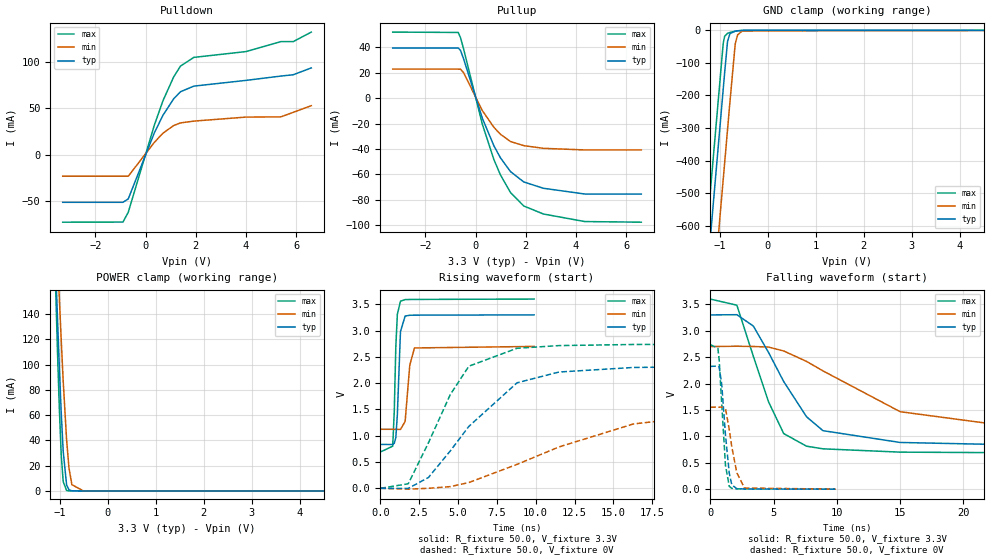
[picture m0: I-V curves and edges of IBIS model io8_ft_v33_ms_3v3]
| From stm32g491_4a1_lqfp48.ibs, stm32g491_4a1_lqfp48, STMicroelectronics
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[Model]   io8_ft_v33_ms_3v3
Model_type I/O
Polarity   Non-Inverting
Enable   Active-Low
| CAP_THRESHOLD on pad IOFT is "UDTCAPC" :
| Rising=30.0% of vddiom   Falling=70.0% of vddiom
| C_comp min and max val. don't necessarily correlate with the min and max pvt
| but are the smallest and greatest pad capacitance found.
| var   typ   min   max
C_comp   2.27946pF  2.25176pF  2.68147pF
|C_comp_pullup   1.26022pF  1.27543pF  1.50397pF
|C_comp_pulldown   1.01925pF  976.33215fF  1.17749pF
Vinl = 810.0mV
Vinh = 2.52V
Vmeas = 1.65V   | Reference voltage for timing measurements
Cref  = 50.0pF   | Timing specification test load capacitance value
Rref  = 100.0MOhm   | Timing specification test load resistance value
Vref  = 1.65V   | Timing specification test load voltage
[Model Spec]
| TIME_THRESHOLD on pin ZIV33M is "CMOS" :
| Rising=50.0% of vddiom   Falling=50.0% of vddiom
Vinl 1.34770V 1.11470V 1.44970V
Vinh 1.77530V 1.49030V 1.90330V
| variable   typ   min   max
[Temperature Range] 25.0 140.0 -40.0
| variable   typ   min   max
[Voltage Range] 3.3V 2.7V 3.6V
| variable   typ   min   max
[POWER Clamp Reference] 3.3V 2.7V 3.6V
| variable   typ   min   max
[GND Clamp Reference] 0V 0V 0V
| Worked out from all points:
|   slope of the pulldown table from 0 to 0.495 V, typ, clamps not added: 15.6 ohm
|   slope of the pullup table from 0 to 0.495 V, typ, clamps not added: 18.1 ohm
|   GND clamp passes 1 mA (typ) near -0.60 V on its own axis
|   POWER clamp passes 1 mA (typ) near -0.81 V on its own axis
|   rising waveform, R_fixture 50.0, V_fixture 3.3V: 20-80 % time 190ps typ, 251ps min, 181ps max; typ from 0.835 V to 3.3 V
|   falling waveform, R_fixture 50.0, V_fixture 3.3V: 20-80 % time 3.64ns typ, 7.54ns min, 2.48ns max; typ from 3.3 V to 0.835 V
|   rising waveform, R_fixture 50.0, V_fixture 0V: 20-80 % time 4.13ns typ, 8.94ns min, 2.71ns max; typ from 0 V to 2.33 V
|   falling waveform, R_fixture 50.0, V_fixture 0V: 20-80 % time 472ps typ, 664ps min, 394ps max; typ from 2.33 V to 0 V
[POWER Clamp]
-3.3V     2.991A     2.546A     3.694A
-1.11V    202.2mA    242.3mA    190.9mA
-1.09V    180mA      223.6mA    163.4mA
-1.05V    136.9mA    187mA      110.9mA
-1.01V    96.55mA    151.6mA    64.02mA
-970mV    60.39mA    117.9mA    27.41mA
-930mV    31.08mA    86.54mA    7.282mA
-860mV    4.779mA    40.5mA     315.2uA
-810mV    823.2uA    18.15mA    29.21uA
-750mV    88.98uA    4.952mA    1.667uA
-510mV    11.25nA    8.405uA    48.77pA
6.6V      0A         0A         0A
[GND Clamp]
-3.3V     -4.209A    -4.487A    -4.067A
-1.41V    -996.3mA   -1.274A    -854.3mA
-1.25V    -724.3mA   -1.002A    -582.3mA
-1.21V    -656.3mA   -933.6mA   -514.3mA
-930mV    -180.3mA   -457.6mA   -39.53mA
-900mV    -129.3mA   -406.6mA   -18.05mA
-840mV    -33.79mA   -304.6mA   -9.105mA
-790mV    -10.15mA   -219.6mA   -6.665mA
-680mV    -2.476mA   -41.57mA   -2.768mA
-630mV    -1.406mA   -13.77mA   -1.51mA
-530mV    -268.4uA   -1.762mA   -214.9uA
6.6V      830.6pA    196nA      594.5pA
| variable   typ   min   max
[Pullup Reference] 3.3V 2.7V 3.6V
| variable   typ   min   max
[Pulldown Reference] 0V 0V 0V
[Pullup]
-3.3V     39.39mA    22.76mA    51.9mA
-690mV    39.39mA    22.76mA    51.61mA
-600mV    37.53mA    22.73mA    47.48mA
-480mV    31mA       20.05mA    38.86mA
270mV     -15.88mA   -9.861mA   -20.62mA
730mV     -37.54mA   -23mA      -48.39mA
990mV     -46.97mA   -28.45mA   -60.4mA
1.39V     -57.81mA   -34.14mA   -74.25mA
1.92V     -65.96mA   -37.41mA   -84.89mA
2.7V      -70.92mA   -39.51mA   -91.15mA
4.35V     -75.45mA   -40.79mA   -97.1mA
6.6V      -75.45mA   -40.79mA   -97.6mA
[Pulldown]
-3.3V     -51.64mA   -23.39mA   -73.18mA
-900mV    -51.64mA   -23.39mA   -73.04mA
-690mV    -47.97mA   -23.39mA   -62.4mA
350mV     23.63mA    13.27mA    31.99mA
690mV     42.49mA    23.17mA    58.21mA
1.12V     60.48mA    31.51mA    84.25mA
1.39V     68.1mA     34.34mA    95.86mA
1.92V     74.17mA    36.28mA    105.3mA
4V        80.41mA    40.64mA    111.6mA
5.39V     85.07mA    40.9mA     122.4mA
5.88V     86.5mA     45.8mA     122.4mA
6.6V      93.9mA     53mA       132.7mA
[Ramp]
dV/dt_r 1.39485V/4.12939ns 931.93273mV/8.94234ns 1.64323V/2.70823ns
dV/dt_f 1.47908V/3.63556ns 946.45341mV/7.54066ns 1.74612V/2.48315ns
R_load = 50.0
| Removed startup time: 0s 0s 0s  .
| Removed end time: 9.9ns.
[Rising Waveform]
R_fixture   = 50.0
V_fixture   = 3.3V
V_fixture_min = 2.7V
V_fixture_max = 3.6V
0s        834.8mV    1.123V     689.8mV
800ps     833mV      1.123V     801.4mV
900ps     856.7mV    1.122V     1.463V
1ns       961.6mV    1.122V     2.691V
1.1ns     1.408V     1.121V     3.312V
1.3ns     2.983V     1.119V     3.56V
1.6ns     3.277V     1.273V     3.59V
1.9ns     3.292V     2.344V     3.592V
2.2ns     3.294V     2.67V      3.593V
9.9ns     3.299V     2.699V     3.6V
| Removed startup time: 0s 0s 0s  .
| Removed end time: 99.9ns.
[Falling Waveform]
R_fixture   = 50.0
V_fixture   = 3.3V
V_fixture_min = 2.7V
V_fixture_max = 3.6V
0s        3.3V       2.7V       3.6V
2.1ns     3.304V     2.707V     3.484V
3.4ns     3.089V     2.702V     2.517V
4.6ns     2.59V      2.691V     1.655V
5.8ns     2.038V     2.617V     1.053V
7.6ns     1.372V     2.42V      814.1mV
8.9ns     1.108V     2.24V      764mV
15ns      884.5mV    1.467V     701.4mV
23ns      844.3mV    1.212V     691.2mV
99.9ns    834.9mV    1.123V     689.8mV
| Removed startup time: 0s 0s 0s  .
| Removed end time: 99.9ns.
[Rising Waveform]
R_fixture   = 50.0
V_fixture   = 0V
V_fixture_min = 0V
V_fixture_max = 0V
0s        -9.504uV   -14.71uV   3.049uV
1.8ns     -1.37mV    -16.23mV   86.42mV
3.1ns     205.8mV    432.9uV    865.8mV
4.5ns     709.5mV    32.16mV    1.78V
5.7ns     1.178V     109.5mV    2.323V
8.8ns     2.007V     454.9mV    2.664V
11.5ns    2.212V     787mV      2.715V
16.3ns    2.299V     1.225V     2.736V
24.2ns    2.323V     1.485V     2.739V
99.9ns    2.325V     1.553V     2.739V
| Removed startup time: 0s 0s 0s  .
| Removed end time: 9.9ns.
[Falling Waveform]
R_fixture   = 50.0
V_fixture   = 0V
V_fixture_min = 0V
V_fixture_max = 0V
0s        2.325V     1.553V     2.739V
600ps     2.331V     1.553V     2.667V
700ps     2.315V     1.553V     2.46V
900ps     1.995V     1.556V     1.634V
1.2ns     1.025V     1.531V     451mV
1.5ns     301.8mV    1.129V     53.29mV
1.7ns     82.29mV    799.8mV    16.34mV
2.1ns     9.374mV    308.2mV    6.208mV
2.7ns     3.834mV    21.97mV    4.617mV
9.9ns     324uV      553.6uV    228.1uV
